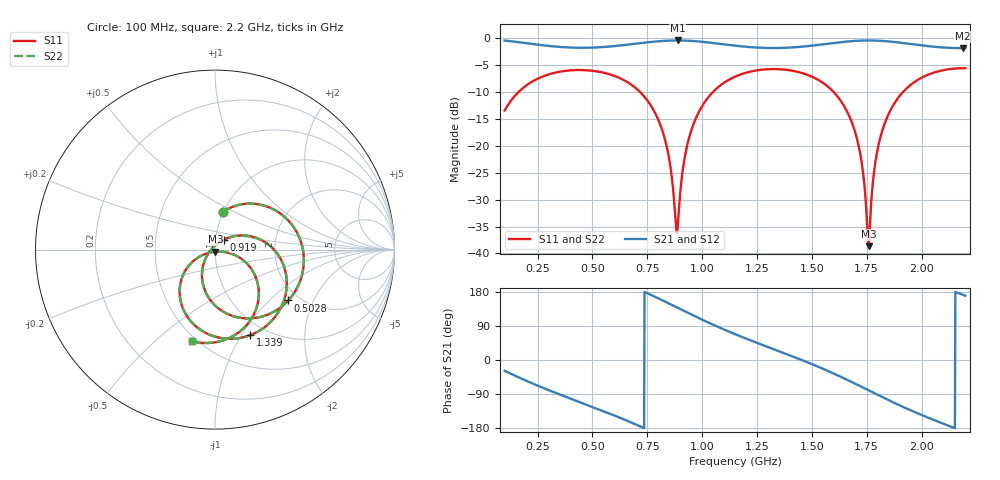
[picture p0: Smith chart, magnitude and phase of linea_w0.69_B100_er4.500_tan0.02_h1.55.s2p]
! Chirptenna · simulación 3D de una microstrip de dos puertos (S12 = S21, S22 = S11 por simetría)
# HZ S RI R 50
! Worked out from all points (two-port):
!   1101 points, 100 MHz to 2.2 GHz, reference 50 ohm
!   highest |S21| = -0.43 dB at 888.5 MHz (marker M1); lowest = -1.9 dB at 2.189 GHz (marker M2)
!   |S21| within 3 dB of the highest: start of sweep to end of sweep
!   lowest |S11| = -38.6 dB at 1.759 GHz (marker M3), VSWR 1.02, Z = 50.2 - j1.15 ohm
!   |S11| at or under -10 dB: start of sweep to 164 MHz; 716.9 MHz to 1.05 GHz (332.8 MHz wide, 37.7 % of centre); 1.599 GHz to 1.916 GHz (316.7 MHz wide, 18 % of centre)
!   |S22| runs from -38.6 to -5.6 dB; largest |S21 - S12| = 0
!   S11 on the Smith chart (normalised r, x): 100 MHz: 0.99, +0.43; 502.8 MHz: 1.75, -1.32; 919 MHz: 1.10, +0.12; 1.339 GHz: 0.84, -1.09; 2.2 GHz: 0.47, -0.66
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1e8  0.0419 0.209  0.8342 -0.4534  0.8342 -0.4534  0.0419 0.209
2.584545e8  0.3854 0.1843  0.3025 -0.8115  0.3025 -0.8115  0.3854 0.1843
4.512727e8  0.4666 -0.1938  -0.3193 -0.7486  -0.3193 -0.7486  0.4666 -0.1938
5.028182e8  0.4082 -0.283  -0.4618 -0.6743  -0.4618 -0.6743  0.4082 -0.283
6.517273e8  0.1277 -0.3776  -0.8059 -0.3155  -0.8059 -0.3155  0.1277 -0.3776
8.006364e8  -0.0721 -0.1584  -0.8924 0.2789  -0.8924 0.2789  -0.0721 -0.1584
8.445455e8  -0.0584 -0.064  -0.8232 0.4686  -0.8232 0.4686  -0.0584 -0.064
8.789091e8  -0.0202 0.000932  -0.7349 0.604  -0.7349 0.604  -0.0202 0.000932
8.884545e8  -0.00582 0.0163  -0.7055 0.6384  -0.7055 0.6384  -0.00582 0.0163
9.19e8  0.0491 0.0553  -0.5994 0.7361  -0.5994 0.7361  0.0491 0.0553
9.991818e8  0.2216 0.0681  -0.2666 0.8862  -0.2666 0.8862  0.2216 0.0681
1.15e9  0.4 -0.1792  0.3156 0.7909  0.3156 0.7909  0.4 -0.1792
1.339e9  0.1951 -0.4771  0.7295 0.3507  0.7295 0.3507  0.1951 -0.4771
1.501273e9  -0.1103 -0.4238  0.8359 -0.1635  0.8359 -0.1635  -0.1103 -0.4238
1.684545e9  -0.1386 -0.0811  0.4864 -0.8031  0.4864 -0.8031  -0.1386 -0.0811
1.726545e9  -0.0656 -0.0287  0.3131 -0.8959  0.3131 -0.8959  -0.0656 -0.0287
1.759e9  0.0023 -0.0115  0.1641 -0.9371  0.1641 -0.9371  0.0023 -0.0115
1.795273e9  0.0803 -0.0191  -0.00817 -0.9479  -0.00817 -0.9479  0.0803 -0.0191
1.850636e9  0.1811 -0.0812  -0.2591 -0.8949  -0.2591 -0.8949  0.1811 -0.0812
2.005273e9  0.2044 -0.3828  -0.711 -0.4738  -0.711 -0.4738  0.2044 -0.3828
2.188545e9  -0.1093 -0.5143  -0.7994 0.1108  -0.7994 0.1108  -0.1093 -0.5143
2.2e9  -0.1308 -0.5091  -0.794 0.1458  -0.794 0.1458  -0.1308 -0.5091
